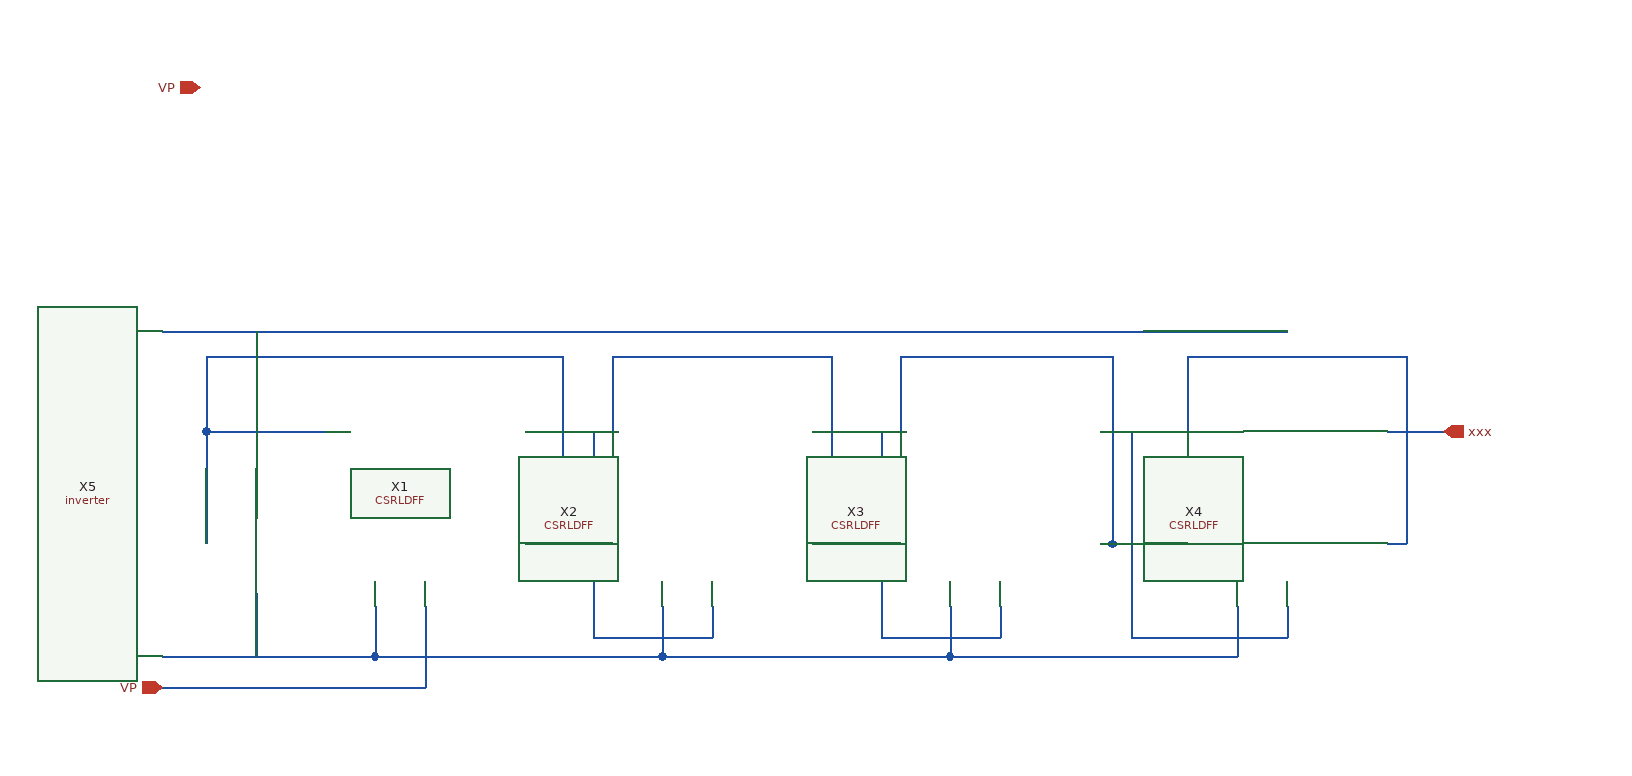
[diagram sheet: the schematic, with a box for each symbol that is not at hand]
v {xschem version=2.9.9 file_version=1.2 }
G {}
K {}
V {}
S {}
E {}
N 80 50 80 115 { lab=#net1}
N 40 50 40 90 { lab=#net2}
N 40 90 270 90 { lab=#net2}
N 270 55 270 90 { lab=#net2}
N 270 50 270 55 { lab=#net2}
N 270 90 500 90 { lab=#net2}
N 500 55 500 90 { lab=#net2}
N 500 50 500 55 { lab=#net2}
N 500 90 730 90 { lab=#net2}
N 730 55 730 90 { lab=#net2}
N 730 50 730 55 { lab=#net2}
N -130 90 40 90 { lab=#net2}
N -130 115 80 115 { lab=#net1}
N -130 -170 770 -170 { lab=#net3}
N -55 40 -55 90 { lab=#net2}
N -55 -170 -55 -40 { lab=#net3}
N -95 -90 -95 -0 { lab=#net4}
N -95 -90 0 -90 { lab=#net4}
N 160 -0 190 -0 { lab=#net4}
N 190 -150 190 -0 { lab=#net4}
N -95 -150 190 -150 { lab=#net4}
N -95 -150 -95 -90 { lab=#net4}
N 190 -0 230 -0 { lab=#net4}
N 310 50 310 75 { lab=#net5}
N 215 75 310 75 { lab=#net5}
N 215 -90 215 75 { lab=#net5}
N 160 -90 215 -90 { lab=#net5}
N 540 50 540 75 { lab=#net6}
N 445 75 540 75 { lab=#net6}
N 445 -90 445 75 { lab=#net6}
N 390 -90 445 -90 { lab=#net6}
N 230 -150 230 -90 { lab=#net7}
N 230 -150 405 -150 { lab=#net7}
N 405 -150 405 -0 { lab=#net7}
N 390 -0 405 -0 { lab=#net7}
N 405 -0 460 -0 { lab=#net7}
N 460 -150 460 -90 { lab=#net8}
N 460 -150 630 -150 { lab=#net8}
N 630 -150 630 -0 { lab=#net8}
N 620 -0 630 -0 { lab=#net8}
N 630 -0 690 -0 { lab=#net8}
N 620 -90 645 -90 { lab=#net9}
N 645 -90 645 45 { lab=#net9}
N 645 45 645 75 { lab=#net9}
N 645 75 770 75 { lab=#net9}
N 770 50 770 75 { lab=#net9}
N 690 -150 690 -90 { lab=#net10}
N 690 -150 865 -150 { lab=#net10}
N 865 -150 865 -0 { lab=#net10}
N 850 -0 865 -0 { lab=#net10}
N 850 -90 895 -90 { lab=xxx}
C {/home/madvlsi/Desktop/MAD_VLSI/FinalProject_DRAM/Schematic/CSRLDFF.sym} -80 10 0 0 {name=X1}
C {/home/madvlsi/Desktop/MAD_VLSI/FinalProject_DRAM/Schematic/CSRLDFF.sym} 150 10 0 0 {name=X2}
C {/home/madvlsi/Desktop/MAD_VLSI/FinalProject_DRAM/Schematic/CSRLDFF.sym} 380 10 0 0 {name=X3}
C {/home/madvlsi/Desktop/MAD_VLSI/FinalProject_DRAM/Schematic/CSRLDFF.sym} 610 10 0 0 {name=X4}
C {/home/madvlsi/Desktop/MAD_VLSI/FinalProject_DRAM/Schematic/inverter.sym} -135 0 0 0 {name = X5}
C {devices/opin.sym} 895 -90 0 0 {name=p1 lab=xxx}
C {devices/iopin.sym} -100 -365 2 0 {name=p2 lab=VP}
C {devices/iopin.sym} -130 115 2 0 {name=p3 lab=VP}
